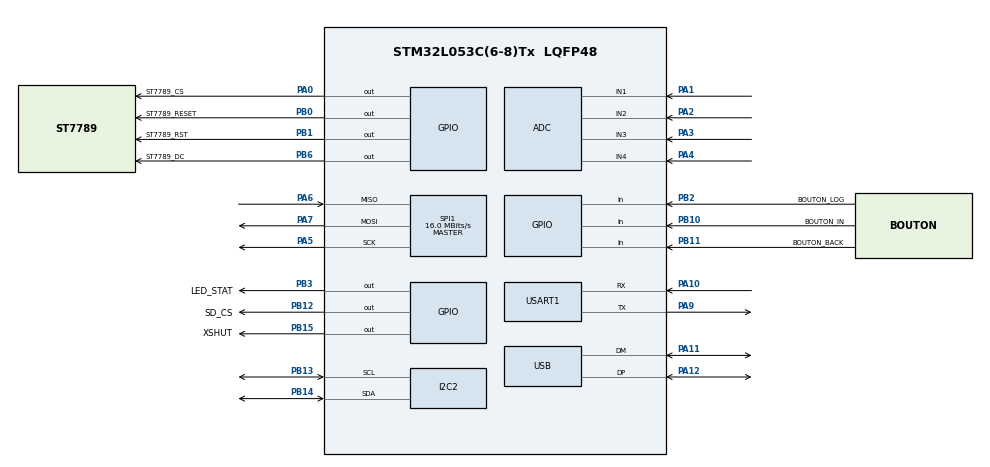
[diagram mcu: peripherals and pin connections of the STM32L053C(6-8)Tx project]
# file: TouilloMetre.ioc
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I2C2.I2C_Fall_Time=100
I2C2.I2C_Rise_Time=100
I2C2.Timing=0x00B07CB4
Mcu.Family=STM32L0
Mcu.Name=STM32L053C(6-8)Tx
Mcu.Package=LQFP48
PA0.GPIO_Label=ST7789_CS
PA0.GPIO_PuPd=GPIO_PULLUP
PA0.GPIO_Speed=GPIO_SPEED_FREQ_LOW
PA0.PinState=GPIO_PIN_SET
PA0.Signal=GPIO_Output
PA1.Mode=IN1
PA1.Signal=ADC_IN1
PA10.Mode=Asynchronous
PA10.Signal=USART1_RX
PA11.Mode=Device
PA11.Signal=USB_DM
PA12.Mode=Device
PA12.Signal=USB_DP
PA13.Mode=Serial_Wire
PA13.Signal=SYS_SWDIO
PA14.Mode=Serial_Wire
PA14.Signal=SYS_SWCLK
PA2.Mode=IN2
PA2.Signal=ADC_IN2
PA3.Mode=IN3
PA3.Signal=ADC_IN3
PA4.Mode=IN4
PA4.Signal=ADC_IN4
PA5.GPIO_PuPd=GPIO_PULLUP
PA5.Mode=Full_Duplex_Master
PA5.Signal=SPI1_SCK
PA6.GPIO_PuPd=GPIO_PULLUP
PA6.Mode=Full_Duplex_Master
PA6.Signal=SPI1_MISO
PA7.GPIO_PuPd=GPIO_PULLUP
PA7.Mode=Full_Duplex_Master
PA7.Signal=SPI1_MOSI
PA9.Mode=Asynchronous
PA9.Signal=USART1_TX
PB0.GPIO_Label=ST7789_RESET
PB0.Signal=GPIO_Output
PB1.GPIO_Label=ST7789_RST
PB1.Signal=GPIO_Output
PB10.GPIO_Label=BOUTON_IN
PB10.Signal=GPIO_Input
PB11.GPIO_Label=BOUTON_BACK
PB11.Signal=GPIO_Input
PB12.GPIO_Label=SD_CS
PB12.GPIO_PuPd=GPIO_PULLUP
PB12.PinState=GPIO_PIN_SET
PB12.Signal=GPIO_Output
PB13.Mode=I2C
PB13.Signal=I2C2_SCL
PB14.Mode=I2C
PB14.Signal=I2C2_SDA
PB15.GPIO_Label=XSHUT
PB15.Signal=GPIO_Output
PB2.GPIO_Label=BOUTON_LOG
PB2.Signal=GPIO_Input
PB3.GPIO_Label=LED_STAT
PB3.Signal=GPIO_Output
PB6.GPIO_Label=ST7789_DC
PB6.Signal=GPIO_Output
PC14-OSC32_IN.Mode=LSE-External-Oscillator
PC14-OSC32_IN.Signal=RCC_OSC32_IN
PC15-OSC32_OUT.Mode=LSE-External-Oscillator
PC15-OSC32_OUT.Signal=RCC_OSC32_OUT
PH0-OSC_IN.Mode=HSE-External-Oscillator
PH0-OSC_IN.Signal=RCC_OSC_IN
PH1-OSC_OUT.Mode=HSE-External-Oscillator
PH1-OSC_OUT.Signal=RCC_OSC_OUT
ProjectManager.HeapSize=0x200
ProjectManager.StackSize=0x400
ProjectManager.TargetToolchain=STM32CubeIDE
RCC.AHBFreq_Value=32000000
RCC.APB1Freq_Value=32000000
RCC.APB1TimFreq_Value=32000000
RCC.APB2Freq_Value=32000000
RCC.APB2TimFreq_Value=32000000
RCC.HCLKFreq_Value=32000000
RCC.HSE_VALUE=8000000
RCC.HSI16_VALUE=16000000
RCC.HSI48_VALUE=48000000
RCC.HSI_VALUE=16000000
RCC.MSI_VALUE=2097000
RCC.PLLDIV=RCC_PLLDIV_3
RCC.PLLMUL=RCC_PLLMUL_12
RCC.SYSCLKFreq_VALUE=32000000
RCC.SYSCLKSource=RCC_SYSCLKSOURCE_PLLCLK
RCC.VCOOutputFreq_Value=96000000
SPI1.BaudRatePrescaler=SPI_BAUDRATEPRESCALER_2
SPI1.CLKPolarity=SPI_POLARITY_HIGH
SPI1.CalculateBaudRate=16.0 MBits/s
SPI1.Direction=SPI_DIRECTION_2LINES
SPI1.Mode=SPI_MODE_MASTER
SPI1.VirtualType=VM_MASTER
USART1.VirtualMode-Asynchronous=VM_ASYNC
VP_FATFS_VS_Generic.Mode=User_defined
VP_RTC_VS_RTC_Activate.Mode=RTC_Enabled
board=custom

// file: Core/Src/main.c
/* USER CODE BEGIN Header */
/**
  ******************************************************************************
  * @file           : main.c
  * @brief          : Main program body
  ******************************************************************************
  * @attention
  *
  * Copyright (c) 2024 STMicroelectronics.
  * All rights reserved.
  *
  * This software is licensed under terms that can be found in the LICENSE file
  * in the root directory of this software component.
  * If no LICENSE file comes with this software, it is provided AS-IS.
  *
  ******************************************************************************
  */
/* USER CODE END Header */
#include "main.h"

ADC_HandleTypeDef hadc;

I2C_HandleTypeDef hi2c2;

RTC_HandleTypeDef hrtc;

SPI_HandleTypeDef hspi1;

UART_HandleTypeDef huart1;

PCD_HandleTypeDef hpcd_USB_FS;

void SystemClock_Config(void);
static void MX_GPIO_Init(void);
static void MX_ADC_Init(void);
static void MX_SPI1_Init(void);
static void MX_USB_PCD_Init(void);
static void MX_RTC_Init(void);
static void MX_USART1_UART_Init(void);
static void MX_I2C2_Init(void);

int main(void)
{

  /* MCU Configuration--------------------------------------------------------*/

  /* Reset of all peripherals, Initializes the Flash interface and the Systick. */
  HAL_Init();

  /* Configure the system clock */
  SystemClock_Config();

  /* Initialize all configured peripherals */
  MX_GPIO_Init();
  MX_ADC_Init();
  MX_SPI1_Init();
  MX_USB_PCD_Init();
  MX_RTC_Init();
  MX_USART1_UART_Init();
  MX_I2C2_Init();

  /* Infinite loop */
  while (1)
  {

  }
}

void SystemClock_Config(void)
{
  RCC_OscInitTypeDef RCC_OscInitStruct = {0};
  RCC_ClkInitTypeDef RCC_ClkInitStruct = {0};
  RCC_PeriphCLKInitTypeDef PeriphClkInit = {0};

  /** Configure the main internal regulator output voltage
  */
  __HAL_PWR_VOLTAGESCALING_CONFIG(PWR_REGULATOR_VOLTAGE_SCALE1);

  /** Initializes the RCC Oscillators according to the specified parameters
  * in the RCC_OscInitTypeDef structure.
  */
  RCC_OscInitStruct.OscillatorType = RCC_OSCILLATORTYPE_HSI|RCC_OSCILLATORTYPE_LSI
                              |RCC_OSCILLATORTYPE_MSI;
  RCC_OscInitStruct.HSIState = RCC_HSI_ON;
  RCC_OscInitStruct.HSICalibrationValue = RCC_HSICALIBRATION_DEFAULT;
  RCC_OscInitStruct.LSIState = RCC_LSI_ON;
  RCC_OscInitStruct.MSIState = RCC_MSI_ON;
  RCC_OscInitStruct.MSICalibrationValue = 0;
  RCC_OscInitStruct.MSIClockRange = RCC_MSIRANGE_5;
  RCC_OscInitStruct.PLL.PLLState = RCC_PLL_ON;
  RCC_OscInitStruct.PLL.PLLSource = RCC_PLLSOURCE_HSI;
  RCC_OscInitStruct.PLL.PLLMUL = RCC_PLLMUL_3;
  RCC_OscInitStruct.PLL.PLLDIV = RCC_PLLDIV_2;
  if (HAL_RCC_OscConfig(&RCC_OscInitStruct) != HAL_OK)
  {
    Error_Handler();
  }

  /** Initializes the CPU, AHB and APB buses clocks
  */
  RCC_ClkInitStruct.ClockType = RCC_CLOCKTYPE_HCLK|RCC_CLOCKTYPE_SYSCLK
                              |RCC_CLOCKTYPE_PCLK1|RCC_CLOCKTYPE_PCLK2;
  RCC_ClkInitStruct.SYSCLKSource = RCC_SYSCLKSOURCE_MSI;
  RCC_ClkInitStruct.AHBCLKDivider = RCC_SYSCLK_DIV1;
  RCC_ClkInitStruct.APB1CLKDivider = RCC_HCLK_DIV1;
  RCC_ClkInitStruct.APB2CLKDivider = RCC_HCLK_DIV1;

  if (HAL_RCC_ClockConfig(&RCC_ClkInitStruct, FLASH_LATENCY_0) != HAL_OK)
  {
    Error_Handler();
  }
  PeriphClkInit.PeriphClockSelection = RCC_PERIPHCLK_USART1|RCC_PERIPHCLK_RTC
                              |RCC_PERIPHCLK_USB;
  PeriphClkInit.Usart1ClockSelection = RCC_USART1CLKSOURCE_PCLK2;
  PeriphClkInit.RTCClockSelection = RCC_RTCCLKSOURCE_LSI;
  PeriphClkInit.UsbClockSelection = RCC_USBCLKSOURCE_PLL;
  if (HAL_RCCEx_PeriphCLKConfig(&PeriphClkInit) != HAL_OK)
  {
    Error_Handler();
  }
}

static void MX_ADC_Init(void)
{

  ADC_ChannelConfTypeDef sConfig = {0};

  /** Configure the global features of the ADC (Clock, Resolution, Data Alignment and number of conversion)
  */
  hadc.Instance = ADC1;
  hadc.Init.OversamplingMode = DISABLE;
  hadc.Init.ClockPrescaler = ADC_CLOCK_SYNC_PCLK_DIV1;
  hadc.Init.Resolution = ADC_RESOLUTION_12B;
  hadc.Init.SamplingTime = ADC_SAMPLETIME_1CYCLE_5;
  hadc.Init.ScanConvMode = ADC_SCAN_DIRECTION_FORWARD;
  hadc.Init.DataAlign = ADC_DATAALIGN_RIGHT;
  hadc.Init.ContinuousConvMode = DISABLE;
  hadc.Init.DiscontinuousConvMode = DISABLE;
  hadc.Init.ExternalTrigConvEdge = ADC_EXTERNALTRIGCONVEDGE_NONE;
  hadc.Init.ExternalTrigConv = ADC_SOFTWARE_START;
  hadc.Init.DMAContinuousRequests = DISABLE;
  hadc.Init.EOCSelection = ADC_EOC_SINGLE_CONV;
  hadc.Init.Overrun = ADC_OVR_DATA_PRESERVED;
  hadc.Init.LowPowerAutoWait = DISABLE;
  hadc.Init.LowPowerFrequencyMode = ENABLE;
  hadc.Init.LowPowerAutoPowerOff = DISABLE;
  if (HAL_ADC_Init(&hadc) != HAL_OK)
  {
    Error_Handler();
  }

  /** Configure for the selected ADC regular channel to be converted.
  */
  sConfig.Channel = ADC_CHANNEL_1;
  sConfig.Rank = ADC_RANK_CHANNEL_NUMBER;
  if (HAL_ADC_ConfigChannel(&hadc, &sConfig) != HAL_OK)
  {
    Error_Handler();
  }

  /** Configure for the selected ADC regular channel to be converted.
  */
  sConfig.Channel = ADC_CHANNEL_2;
  if (HAL_ADC_ConfigChannel(&hadc, &sConfig) != HAL_OK)
  {
    Error_Handler();
  }

  /** Configure for the selected ADC regular channel to be converted.
  */
  sConfig.Channel = ADC_CHANNEL_3;
  if (HAL_ADC_ConfigChannel(&hadc, &sConfig) != HAL_OK)
  {
    Error_Handler();
  }

  /** Configure for the selected ADC regular channel to be converted.
  */
  sConfig.Channel = ADC_CHANNEL_4;
  if (HAL_ADC_ConfigChannel(&hadc, &sConfig) != HAL_OK)
  {
    Error_Handler();
  }

}

static void MX_I2C2_Init(void)
{

  hi2c2.Instance = I2C2;
  hi2c2.Init.Timing = 0x00000708;
  hi2c2.Init.OwnAddress1 = 0;
  hi2c2.Init.AddressingMode = I2C_ADDRESSINGMODE_7BIT;
  hi2c2.Init.DualAddressMode = I2C_DUALADDRESS_DISABLE;
  hi2c2.Init.OwnAddress2 = 0;
  hi2c2.Init.OwnAddress2Masks = I2C_OA2_NOMASK;
  hi2c2.Init.GeneralCallMode = I2C_GENERALCALL_DISABLE;
  hi2c2.Init.NoStretchMode = I2C_NOSTRETCH_DISABLE;
  if (HAL_I2C_Init(&hi2c2) != HAL_OK)
  {
    Error_Handler();
  }

  /** Configure Analogue filter
  */
  if (HAL_I2CEx_ConfigAnalogFilter(&hi2c2, I2C_ANALOGFILTER_ENABLE) != HAL_OK)
  {
    Error_Handler();
  }

  /** Configure Digital filter
  */
  if (HAL_I2CEx_ConfigDigitalFilter(&hi2c2, 0) != HAL_OK)
  {
    Error_Handler();
  }

}

static void MX_RTC_Init(void)
{

  /** Initialize RTC Only
  */
  hrtc.Instance = RTC;
  hrtc.Init.HourFormat = RTC_HOURFORMAT_24;
  hrtc.Init.AsynchPrediv = 127;
  hrtc.Init.SynchPrediv = 255;
  hrtc.Init.OutPut = RTC_OUTPUT_DISABLE;
  hrtc.Init.OutPutRemap = RTC_OUTPUT_REMAP_NONE;
  hrtc.Init.OutPutPolarity = RTC_OUTPUT_POLARITY_HIGH;
  hrtc.Init.OutPutType = RTC_OUTPUT_TYPE_OPENDRAIN;
  if (HAL_RTC_Init(&hrtc) != HAL_OK)
  {
    Error_Handler();
  }

}

static void MX_SPI1_Init(void)
{

  /* SPI1 parameter configuration*/
  hspi1.Instance = SPI1;
  hspi1.Init.Mode = SPI_MODE_MASTER;
  hspi1.Init.Direction = SPI_DIRECTION_2LINES;
  hspi1.Init.DataSize = SPI_DATASIZE_8BIT;
  hspi1.Init.CLKPolarity = SPI_POLARITY_LOW;
  hspi1.Init.CLKPhase = SPI_PHASE_1EDGE;
  hspi1.Init.NSS = SPI_NSS_SOFT;
  hspi1.Init.BaudRatePrescaler = SPI_BAUDRATEPRESCALER_2;
  hspi1.Init.FirstBit = SPI_FIRSTBIT_MSB;
  hspi1.Init.TIMode = SPI_TIMODE_DISABLE;
  hspi1.Init.CRCCalculation = SPI_CRCCALCULATION_DISABLE;
  hspi1.Init.CRCPolynomial = 7;
  if (HAL_SPI_Init(&hspi1) != HAL_OK)
  {
    Error_Handler();
  }

}

static void MX_USART1_UART_Init(void)
{

  huart1.Instance = USART1;
  huart1.Init.BaudRate = 115200;
  huart1.Init.WordLength = UART_WORDLENGTH_8B;
  huart1.Init.StopBits = UART_STOPBITS_1;
  huart1.Init.Parity = UART_PARITY_NONE;
  huart1.Init.Mode = UART_MODE_TX_RX;
  huart1.Init.HwFlowCtl = UART_HWCONTROL_NONE;
  huart1.Init.OverSampling = UART_OVERSAMPLING_16;
  huart1.Init.OneBitSampling = UART_ONE_BIT_SAMPLE_DISABLE;
  huart1.AdvancedInit.AdvFeatureInit = UART_ADVFEATURE_NO_INIT;
  if (HAL_UART_Init(&huart1) != HAL_OK)
  {
    Error_Handler();
  }

}

static void MX_USB_PCD_Init(void)
{

  hpcd_USB_FS.Instance = USB;
  hpcd_USB_FS.Init.dev_endpoints = 8;
  hpcd_USB_FS.Init.speed = PCD_SPEED_FULL;
  hpcd_USB_FS.Init.phy_itface = PCD_PHY_EMBEDDED;
  hpcd_USB_FS.Init.low_power_enable = DISABLE;
  hpcd_USB_FS.Init.lpm_enable = DISABLE;
  hpcd_USB_FS.Init.battery_charging_enable = DISABLE;
  if (HAL_PCD_Init(&hpcd_USB_FS) != HAL_OK)
  {
    Error_Handler();
  }

}

static void MX_GPIO_Init(void)
{
  GPIO_InitTypeDef GPIO_InitStruct = {0};

  /* GPIO Ports Clock Enable */
  __HAL_RCC_GPIOC_CLK_ENABLE();
  __HAL_RCC_GPIOH_CLK_ENABLE();
  __HAL_RCC_GPIOA_CLK_ENABLE();
  __HAL_RCC_GPIOB_CLK_ENABLE();

  /*Configure GPIO pin Output Level */
  HAL_GPIO_WritePin(GPIOA, GPIO_PIN_0, GPIO_PIN_RESET);

  /*Configure GPIO pin Output Level */
  HAL_GPIO_WritePin(GPIOB, GPIO_PIN_0|GPIO_PIN_1|GPIO_PIN_12|GPIO_PIN_15
                          |GPIO_PIN_3|GPIO_PIN_6, GPIO_PIN_RESET);

  /*Configure GPIO pin : PA0 */
  GPIO_InitStruct.Pin = GPIO_PIN_0;
  GPIO_InitStruct.Mode = GPIO_MODE_OUTPUT_PP;
  GPIO_InitStruct.Pull = GPIO_NOPULL;
  GPIO_InitStruct.Speed = GPIO_SPEED_FREQ_LOW;
  HAL_GPIO_Init(GPIOA, &GPIO_InitStruct);

  /*Configure GPIO pins : PB0 PB1 PB12 PB15
                           PB3 PB6 */
  GPIO_InitStruct.Pin = GPIO_PIN_0|GPIO_PIN_1|GPIO_PIN_12|GPIO_PIN_15
                          |GPIO_PIN_3|GPIO_PIN_6;
  GPIO_InitStruct.Mode = GPIO_MODE_OUTPUT_PP;
  GPIO_InitStruct.Pull = GPIO_NOPULL;
  GPIO_InitStruct.Speed = GPIO_SPEED_FREQ_LOW;
  HAL_GPIO_Init(GPIOB, &GPIO_InitStruct);

  /*Configure GPIO pins : PB2 PB10 PB11 */
  GPIO_InitStruct.Pin = GPIO_PIN_2|GPIO_PIN_10|GPIO_PIN_11;
  GPIO_InitStruct.Mode = GPIO_MODE_INPUT;
  GPIO_InitStruct.Pull = GPIO_NOPULL;
  HAL_GPIO_Init(GPIOB, &GPIO_InitStruct);

}

void Error_Handler(void)
{
  __disable_irq();
  while (1)
  {
  }
}
